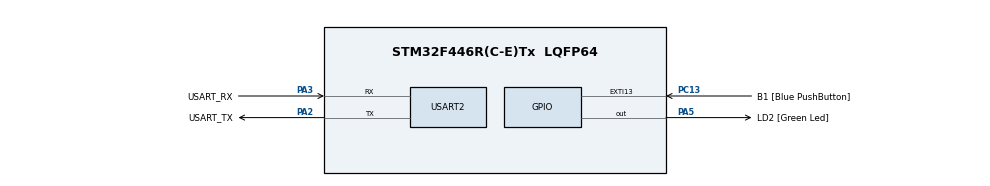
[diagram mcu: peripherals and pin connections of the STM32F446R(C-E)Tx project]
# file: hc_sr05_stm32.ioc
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Mcu.Family=STM32F4
Mcu.Name=STM32F446R(C-E)Tx
Mcu.Package=LQFP64
NVIC.PriorityGroup=NVIC_PRIORITYGROUP_0
PA13.GPIO_Label=TMS
PA13.Mode=Serial_Wire
PA13.Signal=SYS_JTMS-SWDIO
PA14.GPIO_Label=TCK
PA14.Mode=Serial_Wire
PA14.Signal=SYS_JTCK-SWCLK
PA2.GPIO_Label=USART_TX
PA2.Mode=Asynchronous
PA2.Signal=USART2_TX
PA3.GPIO_Label=USART_RX
PA3.Mode=Asynchronous
PA3.Signal=USART2_RX
PA5.GPIO_Label=LD2 [Green Led]
PA5.Signal=GPIO_Output
PB3.GPIO_Label=SWO
PB3.Signal=SYS_JTDO-SWO
PC13.GPIO_Label=B1 [Blue PushButton]
PC13.GPIO_ModeDefaultEXTI=GPIO_MODE_IT_FALLING
PC13.Signal=GPXTI13
PC14-OSC32_IN.Mode=LSE-External-Oscillator
PC14-OSC32_IN.Signal=RCC_OSC32_IN
PC15-OSC32_OUT.Mode=LSE-External-Oscillator
PC15-OSC32_OUT.Signal=RCC_OSC32_OUT
PH0-OSC_IN.Mode=HSE-External-Oscillator
PH0-OSC_IN.Signal=RCC_OSC_IN
PH1-OSC_OUT.Mode=HSE-External-Oscillator
PH1-OSC_OUT.Signal=RCC_OSC_OUT
ProjectManager.HeapSize=0x200
ProjectManager.StackSize=0x400
ProjectManager.TargetToolchain=STM32CubeIDE
RCC.48MHZClocksFreq_Value=84000000
RCC.AHBFreq_Value=180000000
RCC.APB1CLKDivider=RCC_HCLK_DIV4
RCC.APB1Freq_Value=45000000
RCC.APB1TimFreq_Value=90000000
RCC.APB2CLKDivider=RCC_HCLK_DIV2
RCC.APB2Freq_Value=90000000
RCC.APB2TimFreq_Value=180000000
RCC.CortexFreq_Value=180000000
RCC.FLatency-AdvancedSettings=FLASH_LATENCY_5
RCC.HCLKFreq_Value=180000000
RCC.HSE_VALUE=8000000
RCC.HSI_VALUE=16000000
RCC.PLLM=8
RCC.PLLN=180
RCC.SYSCLKFreq_VALUE=180000000
RCC.SYSCLKSource=RCC_SYSCLKSOURCE_PLLCLK
RCC.USBFreq_Value=180000000
RCC.VCOOutputFreq_Value=360000000
USART2.VirtualMode=VM_ASYNC
board=NUCLEO-F446RE

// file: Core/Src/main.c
/* USER CODE BEGIN Header */
/**
  ******************************************************************************
  * @file           : main.c
  * @brief          : Main program body
  ******************************************************************************
  * @attention
  *
  * Copyright (c) 2026 STMicroelectronics.
  * All rights reserved.
  *
  * This software is licensed under terms that can be found in the LICENSE file
  * in the root directory of this software component.
  * If no LICENSE file comes with this software, it is provided AS-IS.
  *
  ******************************************************************************
  */
/* USER CODE END Header */
#include "main.h"

UART_HandleTypeDef huart2;

void SystemClock_Config(void);
static void MX_GPIO_Init(void);
static void MX_USART2_UART_Init(void);

/* USER CODE BEGIN 0 */
volatile uint8_t time_elapsed = 0;
uint16_t counter = 0;
void TIM6_DAC_IRQHandler() {
	if((TIM6->SR >> TIM_SR_UIF_Pos) & 0x01) {
		NVIC_ClearPendingIRQ(TIM6_DAC_IRQn);
		time_elapsed = 1;
		TIM6->CR1 &= ~(1 << TIM_CR1_CEN_Pos);
		TIM6->SR &= ~(1 << TIM_SR_UIF_Pos);
	}
}

uint8_t measure_collected = 0;
uint32_t measure = 0;
void EXTI1_IRQHandler() {
	NVIC_ClearPendingIRQ(EXTI1_IRQn);
	if((GPIOC->IDR >> 1) & 0x01) {
		TIM6->ARR = 65000;
		TIM6->CNT = 0;
		TIM6->CR1 |= (1 << TIM_CR1_CEN_Pos);
		measure_collected = 0;
	} else {
		TIM6->CR1 &= ~(1 << TIM_CR1_CEN_Pos);
		measure = TIM6->CNT;
		measure_collected = 1;
	}
	EXTI->PR |= (0x01 << EXTI_PR_PR1_Pos);
}

void TIM6_basic_setup() {

	RCC->APB1ENR |= (1 << RCC_APB1ENR_TIM6EN_Pos); 		// Clock to TIM6

	TIM6->CR1 &= ~(1 << TIM_CR1_UDIS_Pos); 		// Update event enable
	TIM6->CR1 |= (1 << TIM_CR1_URS_Pos);		// Update event generated only by overflow/underflow
	TIM6->PSC = 90 - 1; 						// CNT incremented every nanoseconds

	TIM6->DIER |= (1 << TIM_DIER_UIE_Pos); 		// Trigger an interrupt every update event
	NVIC_EnableIRQ(TIM6_DAC_IRQn);				// Enable interrupt for TIM6
	NVIC_SetPriority(TIM6_DAC_IRQn, 0); 		// Set Priority
}

void delay_micro_s(uint16_t delay) {
	TIM6->ARR = delay - 1;
	TIM6->CNT = 0;
	TIM6->CR1 |= (1 << TIM_CR1_CEN_Pos);
	while(!time_elapsed) {};
	time_elapsed = 0;
}

void hc_sr04_init() {
	RCC->AHB1ENR |= (1 << RCC_AHB1ENR_GPIOCEN_Pos);
	RCC->APB2ENR |= (1 << RCC_APB2ENR_SYSCFGEN_Pos);

	/** Trigger pin configuration **/
	GPIOC->MODER |= (0x01 << 0);  // Set Output
	// Push-Pull output
	GPIOC->OTYPER &= ~(0x1 << 0);

	/**Echo pin configuration **/
	GPIOC->MODER  &= ~(0x03 << 2); // Set Input

	/* SYStem ConFiGuration (Multiplexer) */
	SYSCFG->EXTICR[0] |= (SYSCFG_EXTICR1_EXTI1_PC);

	/* EXTernal Interrupt configuration */
	EXTI->IMR  |= (EXTI_IMR_IM1);
	EXTI->FTSR |= (0x01 << EXTI_FTSR_TR1_Pos);
	EXTI->RTSR |= (0x01 << EXTI_RTSR_TR1_Pos);

	/* NVIC Configuration */
	NVIC_EnableIRQ(EXTI1_IRQn);
	NVIC_SetPriority(EXTI1_IRQn, 0);

	TIM6_basic_setup();
}

void set_triger() {
	GPIOC->ODR |= (1 << 0);
}

void clear_triger() {
	GPIOC->ODR &= ~(1 << 0);
}

float meas_dist() {
	clear_triger(); 	// keep trigger low
	delay_micro_s(3);	// for at least 3 mu_s

	set_triger();		// set trigger high
	delay_micro_s(10);	// for at least 10 mu_s
	clear_triger();		// clear trigger to start ultrasonic burst transmission

	while(!measure_collected);	// wait for measurement to be collected (look EXTI ISR)
	return 0.5*0.000343*measure;				// return measurement (twice speed of sound times echo rise time)
}
float measure_f;
/* USER CODE END 0 */

int main(void)
{

  /* MCU Configuration--------------------------------------------------------*/

  /* Reset of all peripherals, Initializes the Flash interface and the Systick. */
  HAL_Init();

  /* Configure the system clock */
  SystemClock_Config();

  /* Initialize all configured peripherals */
  MX_GPIO_Init();
  MX_USART2_UART_Init();
  hc_sr04_init();
  /* Infinite loop */
  /* USER CODE BEGIN WHILE */
  while (1)
  {
	  measure_f = meas_dist();
	  HAL_Delay(1000);
    /* USER CODE END WHILE */

  }
}

void SystemClock_Config(void)
{
  RCC_OscInitTypeDef RCC_OscInitStruct = {0};
  RCC_ClkInitTypeDef RCC_ClkInitStruct = {0};

  /** Configure the main internal regulator output voltage
  */
  __HAL_RCC_PWR_CLK_ENABLE();
  __HAL_PWR_VOLTAGESCALING_CONFIG(PWR_REGULATOR_VOLTAGE_SCALE3);

  /** Initializes the RCC Oscillators according to the specified parameters
  * in the RCC_OscInitTypeDef structure.
  */
  RCC_OscInitStruct.OscillatorType = RCC_OSCILLATORTYPE_HSI;
  RCC_OscInitStruct.HSIState = RCC_HSI_ON;
  RCC_OscInitStruct.HSICalibrationValue = RCC_HSICALIBRATION_DEFAULT;
  RCC_OscInitStruct.PLL.PLLState = RCC_PLL_ON;
  RCC_OscInitStruct.PLL.PLLSource = RCC_PLLSOURCE_HSI;
  RCC_OscInitStruct.PLL.PLLM = 16;
  RCC_OscInitStruct.PLL.PLLN = 336;
  RCC_OscInitStruct.PLL.PLLP = RCC_PLLP_DIV4;
  RCC_OscInitStruct.PLL.PLLQ = 2;
  RCC_OscInitStruct.PLL.PLLR = 2;
  if (HAL_RCC_OscConfig(&RCC_OscInitStruct) != HAL_OK)
  {
    Error_Handler();
  }

  /** Initializes the CPU, AHB and APB buses clocks
  */
  RCC_ClkInitStruct.ClockType = RCC_CLOCKTYPE_HCLK|RCC_CLOCKTYPE_SYSCLK
                              |RCC_CLOCKTYPE_PCLK1|RCC_CLOCKTYPE_PCLK2;
  RCC_ClkInitStruct.SYSCLKSource = RCC_SYSCLKSOURCE_PLLCLK;
  RCC_ClkInitStruct.AHBCLKDivider = RCC_SYSCLK_DIV1;
  RCC_ClkInitStruct.APB1CLKDivider = RCC_HCLK_DIV2;
  RCC_ClkInitStruct.APB2CLKDivider = RCC_HCLK_DIV1;

  if (HAL_RCC_ClockConfig(&RCC_ClkInitStruct, FLASH_LATENCY_2) != HAL_OK)
  {
    Error_Handler();
  }
}

static void MX_USART2_UART_Init(void)
{

  huart2.Instance = USART2;
  huart2.Init.BaudRate = 115200;
  huart2.Init.WordLength = UART_WORDLENGTH_8B;
  huart2.Init.StopBits = UART_STOPBITS_1;
  huart2.Init.Parity = UART_PARITY_NONE;
  huart2.Init.Mode = UART_MODE_TX_RX;
  huart2.Init.HwFlowCtl = UART_HWCONTROL_NONE;
  huart2.Init.OverSampling = UART_OVERSAMPLING_16;
  if (HAL_UART_Init(&huart2) != HAL_OK)
  {
    Error_Handler();
  }

}

static void MX_GPIO_Init(void)
{
  GPIO_InitTypeDef GPIO_InitStruct = {0};

  /* GPIO Ports Clock Enable */
  __HAL_RCC_GPIOC_CLK_ENABLE();
  __HAL_RCC_GPIOH_CLK_ENABLE();
  __HAL_RCC_GPIOA_CLK_ENABLE();
  __HAL_RCC_GPIOB_CLK_ENABLE();

  /*Configure GPIO pin Output Level */
  HAL_GPIO_WritePin(LD2_GPIO_Port, LD2_Pin, GPIO_PIN_RESET);

  /*Configure GPIO pin : B1_Pin */
  GPIO_InitStruct.Pin = B1_Pin;
  GPIO_InitStruct.Mode = GPIO_MODE_IT_FALLING;
  GPIO_InitStruct.Pull = GPIO_NOPULL;
  HAL_GPIO_Init(B1_GPIO_Port, &GPIO_InitStruct);

  /*Configure GPIO pin : LD2_Pin */
  GPIO_InitStruct.Pin = LD2_Pin;
  GPIO_InitStruct.Mode = GPIO_MODE_OUTPUT_PP;
  GPIO_InitStruct.Pull = GPIO_NOPULL;
  GPIO_InitStruct.Speed = GPIO_SPEED_FREQ_LOW;
  HAL_GPIO_Init(LD2_GPIO_Port, &GPIO_InitStruct);

}

void Error_Handler(void)
{
  __disable_irq();
  while (1)
  {
  }
}
